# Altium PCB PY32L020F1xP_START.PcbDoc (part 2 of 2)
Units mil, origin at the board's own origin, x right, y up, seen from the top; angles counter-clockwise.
Board outline 1771.65 x 3929.06 mil, 2 copper layers (Top Layer, Bottom Layer), stack 21 mil thick; 129 components, 114 nets, 456 pads, 229 vias.
Unrouted connection lines stored in the file: 5.

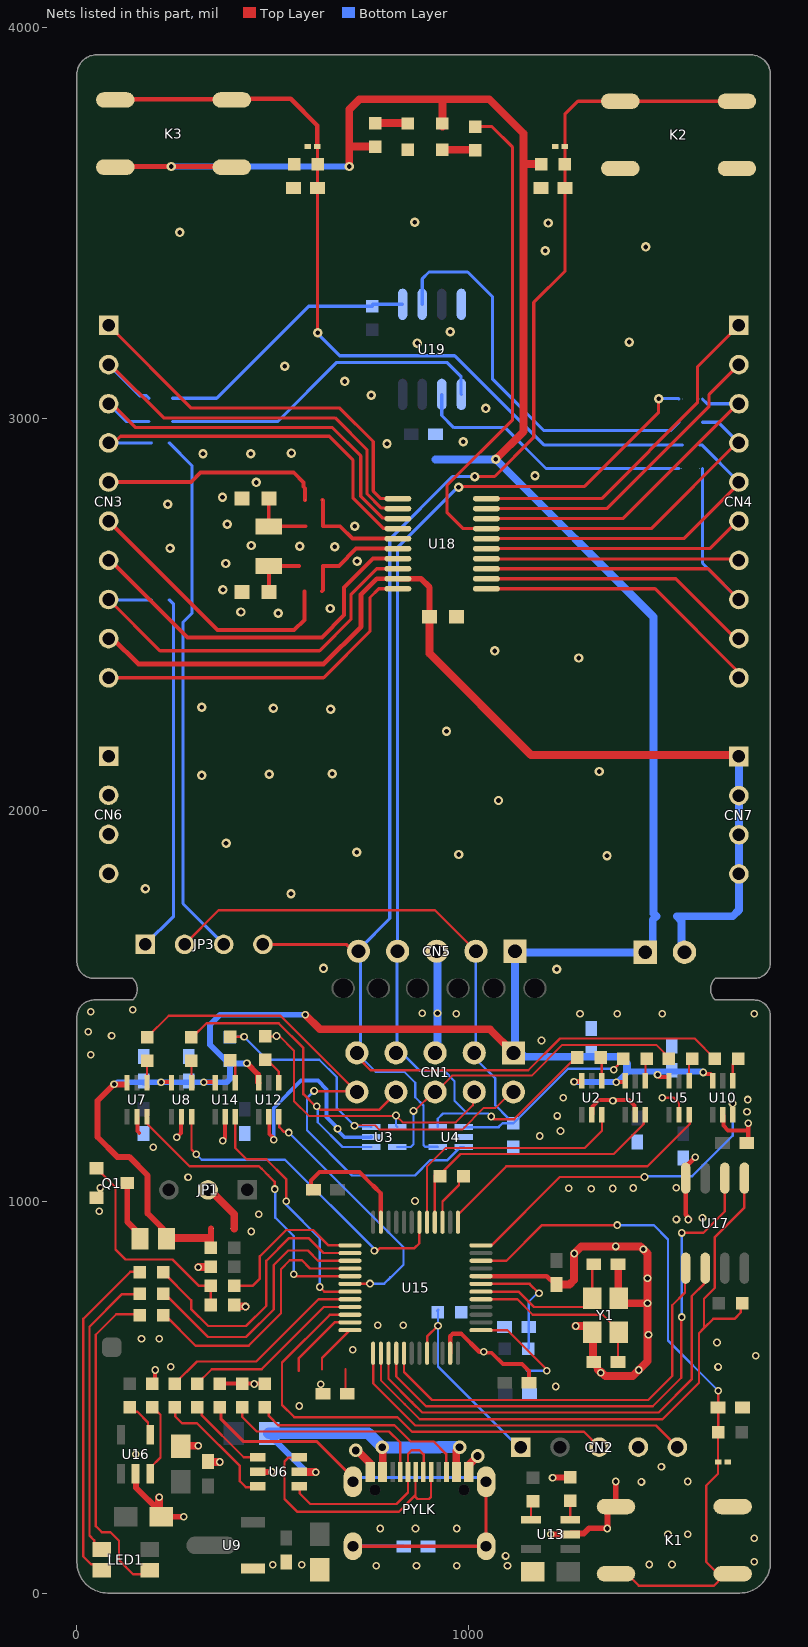
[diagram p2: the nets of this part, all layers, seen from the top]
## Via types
v1: diameter 19.68, hole 11.81, Top Layer to Bottom Layer, tented both sides, 114 vias
v2: diameter 24, hole 12, Top Layer to Bottom Layer, tented both sides, 61 vias
v3: diameter 19.68, hole 11.81, Top Layer to Bottom Layer, 42 vias
v4: diameter 35, hole 20, Top Layer to Bottom Layer, tented both sides, 8 vias
v5: diameter 30, hole 15, Top Layer to Bottom Layer, tented both sides, 2 vias
v6: diameter 40, hole 20, Top Layer to Bottom Layer, tented both sides, 2 vias

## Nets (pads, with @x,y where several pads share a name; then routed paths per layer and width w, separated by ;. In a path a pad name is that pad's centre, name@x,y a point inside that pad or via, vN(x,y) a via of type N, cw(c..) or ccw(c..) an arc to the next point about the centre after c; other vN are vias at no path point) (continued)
GND: C1.1 C2.1 C3.1 C4.1 C5.1 C6.1 C7.1 C8.1 C9.1 C10.1 C11.1 C12.1 C13.1 C14.1 C15.1 C16.1 C17.1 C18.1 C19.1 C20.1 C21.1 C22.1 C23.1 C24.1 C25.1 C26.1 C27.1 C28.1 C29.1 C30.2 C31.1 CN1.5 CN2.4 CN3.7 CN5.3 CN6.1 CN6.2 CN6.3 CN6.4 K1.3 K1.4 K2.3 K2.4 LED_VDD*.2 PYLK.A1 PYLK.A12 PYLK.B1 PYLK.B12 Q1.2 R1.1 R3.2 R5.1 R8.2 R20.1 R21.1 R25.1 R28.2 R30.1 R33.2 R56.1 U1.2 U2.2 U3.2 U4.2 U5.2 U6.2 U7.2 U8.2 U9.1 U10.2 U11.2 U12.2 U13.2 U14.2 U15.8 U15.23 U15.47 U16.2 U17.4 U18.7 U19.4 U20.2 U21.2 Y1.2 Y1.4 | length 5396.9
  Top Layer w6: v1(1495,1265) 1525,1265 1538.06,1251.94 U5.2@1538.06,1221.69
  Top Layer w10: CN3.7@81,2638 85.71,2638 282.96,2440.75 625.55,2440.75 682.73,2497.93 682.73,2568.68 756.63,2642.58 U18.7@819.59,2642.58 ; U7.2@153.55,1216.69 154.54,1215.7 154.54,1180.08 159.36,1175.25 ; R30.1@200,540 v1(200,570) ; C16.1@210,210 210,200 C16.1@215,195 ; v1(255,1164.6) 265.89,1175.49 265.89,1215.32 U8.2@267.26,1216.69 ; C2.1@265,375 C2.1@270,380 ; C3.1@335,336 C3.1@336,335 ; R8.2@365,535 v1@453.95,535 ; v1(372.9,1155.7) 378.59,1161.39 U14.2@378.59,1216.59 ; R20.1@401.52,735.88 R20.1@403.04,737.4 ; v1(453.1,534.15) v1@453.95,535 ; R3.2@480,535 v1@453.95,535 ; U12.2@490.12,1216.69 491.41,1215.4 491.41,1172.62 501.83,1162.2 501.83,1156.83 v1@500,1155 ; C21.1@593.36,1020 603.36,1030 C21.1@604,1030 597.95,1036.05 597.95,1054.14 619.23,1075.42 721.98,1075.42 756.82,1040.58 ; C17.1@628.59,509.5 C17.1@629.59,510.5 ; PYLK.A1@743.31,309.89 PYLK.B12@755.12,309.89 ; PYLK.B1@995.28,309.89 PYLK.A12@1007.09,309.89 ; v1@1039.47,613.56 v1@1039.6,613.69 ; v1@1041.61,614.02 1059.36,614.02 1088.57,584.8 1137.07,584.8 1154.91,566.95 C20.1@1154.87,537.59 ; U2.2@1314.26,1220.75 1317.1,1223.58 1317.1,1242.95 1334.15,1260 v1@1370.02,1260 ; v1(1369.2,1257.6) 1370.02,1258.42 v1@1370.02,1260 ; U1.2@1426.64,1221.69 1424.75,1223.58 1424.75,1245.25 1410,1260 v1@1370.02,1260 ; U10.2@1649.49,1221.69 1651.38,1219.8 1651.38,1193.96 1663.61,1181.72 1715,1181.72
  Top Layer w11: 756.82,1040.58 776.42,1020.98 U15.23@776.42,947.32 ; U15.47@953.58,612.68 953.58,655.91 959.74,662.07 982.08,662.07 1027.87,616.28 v1(1039.35,616.28) ; U15.8@1032.32,809.53 1199.94,809.53 1221.47,788 C22.1@1225.12,788
  Top Layer w12: Q1.2@50.2,1009.8 Q1.2@55.01,1004.99 ; v1(1561.71,954.27) 1566.84,954.27 1555,966.11 1555,1088.88 1579.39,1113.27 v1(1579.39,1113.51) ; C18.1@1711,1150 1715,1154 1715,1181.72 v1(1715,1200)
  Top Layer w15: U16.2@149.48,304.48 150.91,303.04 150.91,269.09 C16.1@210,210 ; C16.1@215,195 v1(272.56,195) ; U6.2@470.66,310.05 472.24,308.47 473.29,309.52 v1(498.08,309.52) ; v1(1210,150) U13.2@1260,150 1262.16,152.16 1294.66,152.16 1308.23,165.74 v1@1354.26,165.74 ; v1(1215,295) R25.1@1260,295 ; v1(1355,165) 1355,209.44 1366.26,220.7 1376.55,220.7 v1(1376.55,285)
  Top Layer w20: C16.1@210,210 v1(210,245) ; C2.1@270,380 273.84,376.16 v1(310,376.16) ; v1(309.83,832.29) 310.59,833.04 341.17,833.04 R21.1@341.93,833.8 ; C3.1@336,335 v1(365,335) ; R20.1@403.04,737.4 403.04,737.12 407.52,732.64 429.94,732.64 v1(430.7,731.87) ; v4(712.08,364.5) 715.53,364.5 PYLK.A1@749.17,330.85 ; CN1.5@915,1380 CN1.5@922.47,1387.47 ; PYLK.A12@1003.89,330.35 v4(1023.55,350) ; C22.1@1220.12,797 1225.12,792 C22.1@1225.12,788 1225.41,788.28 1258.41,788.28 1270.12,800 v1(1270.12,867.57) 1288.1,885.55 1439.57,885.55 1457.58,867.54 v1(1457.58,803.85) 1457.58,740.13 1457.58,592.46 v1(1435.12,570) 1419.85,554.73 1349.89,554.73 v1@1339.64,564.98 ; v1(1273.98,682.29) 1301.06,682.29 Y1.2@1316.66,666.69 1318.39,664.96 1318.39,591.73 C19.1@1320.12,590 1324.12,590 1329.12,585 1329.12,575.5 1330.37,574.25 ; 1330.37,570.63 v1(1337.83,563.18) ; C25.1@1382.12,840 1382.85,839.27 1382.85,754.04 Y1.4@1383.59,753.31 1396.74,740.16 v1(1457.55,740.16)
  Bottom Layer w6: v1@499.26,1157.83 v1(502.89,1157.83)
  Bottom Layer w10: v1(502.89,1157.83) 502.89,1239.49 572.46,1309.06 615.72,1309.06 638,1286.78 638,1215.79 665.89,1187.9 v1(665.89,1185.89) ; v1@665,1183 683.72,1164.28 750.81,1164.28 U3.2@751.54,1165
  Bottom Layer w20: CN1.5@915,1380 921,1386 v3(921,1481) 921,1637.82 CN5.3@919.26,1639.56 ; CN5.3@921,1639.56 CN5.3@921,1642.94
  other v1: 765,70 867.5,70 970,70 1100,70 1462.25,73 1520,73 1730,80 1095,95 1730,140 1510,150 1560,150 775,165 865,165 970,165 1442,284 1560,285 1493,323 150,355 1637.74,577.74 1734,606 1635,640 165,650 210,650 1460.12,660 1447.03,878.1 1376.26,885.55 57.3,975.34 60,1035 1182.35,1167.57 1241.94,1264.95 35,1375 1285,1480 1380,1480 1495,1480 1730,1480 35,1485 143,1490
  other v2: 1226,1593.58 630,1595.58 547,1786.58 175,1799 1354,1883.58 975,1886.58 715,1892.58 381,1915.58 1077,2024.58 319,2088.58 491,2091.58 652,2092.58 1334,2098.58 944,2201.58 648,2257.58 502,2260.58 319,2262.58 1282,2388.58 1067,2406.58 514,2503 419,2506 647,2515 373,2563 380,2630 715.68,2635.32 238,2669 659,2673 569,2674 445,2676 710,2725 384,2730 232,2781 372,2799 458,2837 1170,2854 322,2910 444,2910 548,2912 792,2936 987,2941 1044,3026 752,3060 684,3095 531,3134 869,3193 1411,3195.58 954,3222 1196,3428.58 1453,3438.58 263,3475.58 1204,3499.58 863,3501.58
  other v3: 500.23,72.73 574.48,72.72 568,478 1223.05,527.77 622.75,533.15 239.93,578.18 704.43,621.59 833.63,683.94 768.47,684.5 445.71,923.68 1531.33,954.53 1597.76,958.38 464.86,967.62 863.55,1001.58 1313.59,1033.06 1368.58,1033.45 1256.66,1033.84 1421.24,1034.63 1530.67,1035.55 284,1062 195,1139 1235.29,1180.47 1227.19,1218.9 1711.69,1229.78 1713.32,1260.65 1186.59,1411.54 88.6,1424 29.3,1434.1 969,1480 882,1481
L_USB_CN_DM: PYLK.A7 PYLK.B7 U6.4 | length 510.1
  Top Layer w6: U6.4@568.15,272.6 569.18,271.57 569.18,254.46 596.04,227.6 816.36,227.6 845.67,256.9 845.67,355.67 855,365 875,365 885.71,354.29 885.71,310.57 PYLK.A7@885.04,309.89
L_USB_CN_DP: PYLK.A6 PYLK.B6 U6.6 | length 675.9
  Top Layer w6: U6.6@568.15,347.4 567.26,346.51 540.39,346.51 530.35,336.47 530.35,240.4 563.22,207.53 822.27,207.53 864.95,250.21 ; PYLK.A6@864.95,309.48 864.95,250.21 ; PYLK.B6@904.31,309.48 904.31,245.56 899.06,240.31 870.05,240.31 864.95,245.41 864.95,250.21
LED_BLUE: R9.2 U15.28 | length 675.2
  Top Layer w6: R9.2@220,710 225.04,710 303.26,631.77 438.53,631.77 521.33,714.58 521.33,827.41 543.92,850 575,850 595.79,829.21 U15.28@697.68,829.21
LED_GREEN: R6.2 U15.26 | length 724.3
  Top Layer w6: R6.2@220,820 291.82,748.18 291.82,725.67 335.36,682.13 432.27,682.13 483.48,733.34 483.48,848.48 541.75,906.75 591.91,906.75 630.07,868.58 U15.26@697.68,868.58
LED_RED: R4.2 U15.27 | length 692.2
  Top Layer w6: R4.2@220,765 224.07,765 335.03,654.04 432.13,654.04 502.68,724.59 502.68,837.68 540,875 590,875 616.1,848.9 U15.27@697.68,848.9
NetC1_2: C1.2 PYLK.1 PYLK.2 PYLK.3 PYLK.4 R8.1 | length 1425.4
  Top Layer w8: R8.1@365,475 368.29,471.71 368.29,443.87 424.64,387.52 611.97,387.52 705.12,294.37 PYLK.1@705.12,284.29 ; PYLK.3@705.12,119.73 PYLK.4@1045.28,119.73 PYLK.2@1045.28,284.29
  Bottom Layer w8: PYLK.3@705.12,119.73 834.27,119.73 C1.2@835,119 ; PYLK.1@716.04,295.21 PYLK.2@1034.36,295.21
  Bottom Layer w20: PYLK.1@705.12,284.29 PYLK.1@716.04,295.21 ; PYLK.2@1034.36,295.21 PYLK.2@1045.28,284.29
NetC17_2: C17.2 R31.2 | length 64.1
  Top Layer w6: 686.21,571.75 686.21,513.88 C17.2@690.59,509.5
NetC29_2: C29.2 R49.1 Y2.1 | length 166.6
  Top Layer w10: C29.2@490.5,2796 490,2795.5 Y2.1@490,2724.2 490.8,2725 R49.1@584.24,2725
NetC30_1: C30.1 R50.1 Y2.2 | length 144.1
  Top Layer w10: C30.1@490.5,2557 490.5,2623.3 Y2.2@490,2623.81 566.81,2623.81 567,2624
NetC31_2: C31.2 K3.3 K3.4 R55.1 R56.2 U21.1 | length 2132.1
  Top Layer w8: v2(615,3219) C31.2@615,3589 R56.2@615,3650 U21.1@615,3695
  Top Layer w12: K3.4@92,3815.59 390,3815.59 391.76,3817.35 545.65,3817.35 614.3,3748.7 U21.1@614.3,3695
  Bottom Layer w8: v2(615,3219) 615,3217 671.32,3160.68 964.97,3160.68 1192.65,2933 R55.1@1546.25,2933
NetCN3_5: CN3.5 R39.2 | length 564.9
  Top Layer w10: CN3.5@81,2838 292,2838 316,2862 554,2862 579,2837 579,2826 582.97,2822.03 R39.2@582.97,2792.03
NetCN3_6: CN3.6 R40.2 | length 698.9
  Top Layer w10: CN3.6@81,2738 359,2460 555,2460 580.97,2485.97 580.97,2559.03
NetJP3_1: JP3.1 R51.1 | length 914.5
  Bottom Layer w8: JP3.1@175,1657 247,1729 247,2525.75 R51.1@235.75,2537
NetJP3_3: JP3.3 R44.1 | length 1357.7
  Bottom Layer w8: R44.1@235.75,2938 294,2879.75 294,2503 271,2480 271,1761 JP3.3@375,1657
NetLED1_2: LED1.2 R9.1 | length 846.1
  Top Layer w6: R9.1@160,710 157.67,712.33 100.33,712.33 48,660 48,171 63.8,155.2 85.86,155.2 107.53,133.53 107.53,84.16 143.82,47.87 175.08,47.87 LED1.2@186.02,58.82
NetLED1_3: LED1.3 R6.1 | length 884.3
  Top Layer w6: LED1.3@44.28,58.52 LED1.3@58.98,43.82 ; LED1.3@63.98,58.82 49.28,73.52 36.09,73.52 16,93.61 16,700.34 136.59,820.93 159.07,820.93 R6.1@160,820
NetLED1_4: LED1.4 R4.1 | length 755.1
  Top Layer w6: LED1.4@56.66,98.5 44.36,110.81 44.36,134.74 32,147.09 32,680.34 115.39,763.73 158.73,763.73 R4.1@160,765
NetLED_PA1_2: LED_PA1.2 R53.1 | length 84
  Top Layer w20: LED_PA1.2@933,3687 R53.1@1017,3687
NetLED_VDD*_1: LED_VDD*.1 R38.1 | length 83
  Top Layer w20: R38.1@762,3754.89 LED_VDD*.1@845,3754.89
NetPYLK_A5: PYLK.A5 R1.2 | length 530.3
  Top Layer w6: R1.2@422.49,474.99 422.49,449.82 459.51,412.79 797.58,412.79 825.99,384.38 PYLK.A5@825.99,309.89
NetPYLK_B5: PYLK.B5 R3.1 | length 566
  Top Layer w6: R3.1@480,475 490.31,464.69 490.31,452.34 513.85,428.8 811.11,428.8 852.66,387.24 911.55,387.24 943.17,355.62 943.17,310.82 PYLK.B5@944.1,309.89
NetQ1_1: Q1.1 R19.1 R20.2 | length 559
  Top Layer w6: Q1.1@50,1084.8 51.97,1084.8 63.72,1073.06 63.72,1071.23 98.46,1036.49 98.46,877.34 123.86,851.94 244.45,851.94 311.61,784.78 R19.1@341.53,784.78 ; R20.2@341.52,735.88 R19.1@341.52,784.77
NetQ1_3: Q1.3 R15.1 | length 166.5
  Top Layer w6: Q1.3@125.49,1044.15 Q1.3@128.74,1047.4 ; R15.1@161.54,905 R15.1@161.54,910.91
  Top Layer w15: Q1.3@128.74,1047.4 128.74,948.28 161.54,915.49 R15.1@161.54,905
NetR2_1: R2.1 U1.4 | length 57.9
  Top Layer w6: U1.4@1452.23,1308.31 1452.23,1362.02 R2.1@1455.21,1365
NetR7_1: R7.1 U2.4 | length 57.8
  Top Layer w6: R7.1@1338.06,1365 1340.8,1362.27 U2.4@1340.8,1308.31
NetR10_1: R10.1 U5.4 | length 60.3
  Top Layer w6: U5.4@1563.66,1308.31 1563.66,1356.3 R10.1@1572.35,1365
NetR11_1: R11.1 U6.3 | length 332.9
  Top Layer w6: R11.1@250,475 250.77,474.23 250.77,451.69 268.41,434.05 306.8,434.05 416.24,324.61 416.24,285.87 431.63,270.48 459.74,270.48 U6.3@461.53,272.28
NetR12_1: R12.1 U6.1 | length 227.7
  Top Layer w6: R12.1@308.75,480 319.15,469.6 319.15,453.68 426,346.83 U6.1@471.97,346.83
NetR13_1: R13.1 U7.4 | length 59
  Top Layer w6: R13.1@173.55,1360 179.14,1354.41 U7.4@179.14,1303.31
NetR14_1: R14.1 U8.4 | length 60.8
  Top Layer w6: R14.1@280.94,1360.02 R14.1@290.82,1350.14 ; U8.4@292.86,1303.31 R14.1@292.86,1350.12
NetR18_1: R18.1 U10.4 | length 62.7
  Top Layer w6: U10.4@1675.08,1308.31 1675.08,1350.59 R18.1@1689.49,1365
NetR22_1: R22.1 U12.4 | length 75.3
  Top Layer w6: R22.1@481.63,1362.11 485.62,1362.11 515.71,1332.03 U12.4@515.71,1303.31
NetR24_2: R24.2 U13.4 | length 49.6
  Top Layer w6: U13.4@1160,187.5 1160,230 R24.2@1165,235
NetR25_2: R25.2 U13.3 | length 47.5
  Top Layer w6: U13.3@1260,187.5 R25.2@1260,235
NetR26_1: R26.1 U14.4 | length 62.8
  Top Layer w6: R26.1@391.2,1360.7 404.28,1347.62 U14.4@404.28,1303.31
NetR27_2: R27.2 U15.1 | length 263.8
  Top Layer w6: U15.1@1032.32,671.73 1099.27,671.73 1200,571 v3(1200,568)
  Bottom Layer w6: R27.2@1149.03,569.03 1150.05,568 v3(1200,568)
NetR29_2: R29.2 U16.4 | length 96.1
  Top Layer w6: R29.2@135,475 147,463 154.44,463 181.5,435.94 181.5,411 U16.4@187.5,405
NetR30_2: R30.2 U16.3 | length 190
  Top Layer w6: U16.3@187.5,305 187.5,320 213.56,346.06 213.56,455.68 207.24,462 206,462 R30.2@193,475
NetR31_1: R31.1 U15.36 | length 129.6
  Top Layer w6: 626.21,571.75 626.21,600.26 U15.36@697.68,671.73
NetR33_1: R33.1 U15.35 | length 201.4
  Top Layer w6: 566.96,567.4 566.96,600.38 658,691.42 U15.35@697.68,691.42
NetR43_1: R43.1 R45.1 U19.1 | length 685.3
  Bottom Layer w8: 244,3052 357,3052 592,3287 R43.1@755,3287 ; R43.1@755,3292 U19.1@832,3292
NetR46_1: R46.1 U19.2 | length 1028.3
  Bottom Layer w8: U19.2@882,3292 882,3357 899.53,3374.53 997.98,3374.53 1062.02,3310.49 1062.02,3100.21 1192.97,2969.26 1516.38,2969.26 1538,2990.88
NetR47_2: R47.2 U19.6 | length 716
  Bottom Layer w8: U19.6@932,3062 932,3008 963,2977 1093.91,2977 1198.16,2872.75 1537.99,2872.75
NetR48_2: R48.2 U19.5 | length 860.8
  Bottom Layer w8: 244.01,2992.26 512.34,2992.26 663.83,3143.76 944.99,3143.76 981.41,3107.35 981.41,3062.59 U19.5@982,3062
OSCIN32: R39.1 R49.2 U18.5 | length 271.5
  Top Layer w10: R39.1@627.75,2792 629.02,2790.73 R49.2@629.02,2724.97 672.03,2724.97 703.59,2693.41 U18.5@819.94,2693.41
OSCOUT32: R40.1 R50.2 U18.6 | length 275.4
  Top Layer w10: 625.75,2559 629.02,2562.26 R50.2@629.02,2623.97 668.97,2623.97 712.82,2667.82 U18.6@819.94,2667.82
PA0: CN4.5 R55.2 U18.16 | length 846.6
  Top Layer w8: U18.16@1046,2693.41 1550.52,2693.41 1691,2833.89 CN4.5@1691,2838
  Bottom Layer w8: R55.2@1591.03,2933.03 1595.97,2933.03 CN4.5@1691,2838
PA1: CN4.4 R46.2 R53.2 U18.17 | length 2093.9
  Top Layer w8: R53.2@1018,3746 1059.89,3746 1113,3692.89 1113,2997 945,2829 945,2761 987,2719 U18.17@1046,2719.01 1467.21,2719 1686.21,2938 CN4.4@1691,2938
  Bottom Layer w8: 1598,2990.88 1638.12,2990.88 1680,2949 1691,2949 CN4.4@1691,2938
PA3: CN4.2 U18.19 | length 822.4
  Top Layer w8: U18.19@1046,2770.19 1353.61,2770.18 1615,3031.57 1615,3062 CN4.2@1691,3138 CN4.2@1691,3130.8
PA4: CN4.1 U18.20 | length 881.8
  Top Layer w8: U18.20@1046,2795.78 1340.36,2795.77 1585,3040.41 1585,3132 CN4.1@1691,3238
PA5: CN3.1 U18.1 | length 996.2
  Top Layer w8: CN3.1@81,3238 292.13,3026.87 671.53,3026.87 757,2941.4 757,2814.88 776.11,2795.77 U18.1@819.94,2795.78
PA6: CN3.2 R45.2 U18.2 | length 1095.6
  Top Layer w8: CN3.2@81,3138 85.61,3138 221.82,3001.79 659.68,3001.79 741,2920.46 741,2808.25 777.86,2771.39 818.73,2771.39 U18.2@819.94,2770.19
  Bottom Layer w8: CN3.2@81,3138 160.69,3058.31 177.69,3058.31 184,3052
PA7: CN3.3 R48.1 U18.3 | length 1042.9
  Top Layer w8: CN3.3@81,3038 89.2,3038 150.08,2977.12 652.76,2977.12 725,2904.88 725,2801.63 780.83,2745.8 818.73,2745.8 U18.3@819.94,2744.6
  Bottom Layer w8: CN3.3@81,3038 126.74,2992.26 184.01,2992.26
PB0: CN4.6 U18.15 | length 674.1
  Top Layer w8: U18.15@1046,2667.82 1616.39,2667.82 1686.57,2738 CN4.6@1691,2738
PB1: CN4.7 U18.14 | length 647.8
  Top Layer w8: U18.14@1046.39,2642.61 U18.14@1046,2642.23 1047.21,2641.02 1687.98,2641.02 CN4.7@1691,2638 CN4.7@1690.61,2637.61
PB2: CN4.8 R47.1 U18.13 | length 1050.8
  Top Layer w8: U18.13@1046,2616.64 1612.36,2616.64 CN4.8@1691,2538
  Bottom Layer w8: 1597.99,2872.75 1597.99,2631.01 CN4.8@1691,2538
PB3: CN4.9 U18.12 | length 708.4
  Top Layer w8: U18.12@1046,2591.05 1530,2591.05 1683.05,2438 CN4.9@1691,2438
PB4: CN4.10 U18.11 | length 747.1
  Top Layer w8: U18.11@1046,2565.46 1477,2565.46 1691,2351.46 CN4.10@1691,2338
PB5: CN3.10 U18.10 | length 883.9
  Top Layer w8: CN3.10@81,2338 630.08,2338 748.55,2456.48 748.55,2543.11 770.9,2565.46 U18.10@819.94,2565.46
PB6: CN3.8 R51.2 U18.8 | length 1027.7
  Top Layer w8: CN3.8@81,2538 212,2407 620,2407 699.73,2486.73 699.73,2550.34 766.03,2616.64 U18.8@819.94,2616.64
  Bottom Layer w8: CN3.8@81,2538 82.03,2536.97 R51.2@190.97,2536.97
PC0: CN3.4 R44.2 U18.4 | length 1010.6
  Top Layer w8: CN3.4@81,2938 94.21,2938 111.21,2955 644.66,2955 705,2894.66 705,2797.63 782.67,2719.96 818.97,2719.96 U18.4@819.94,2719.01
  Bottom Layer w8: CN3.4@81,2938 R44.2@190.97,2937.97
PYLK_BOOT0: CN2.1 R28.1 U15.44 | length 514.4
  Top Layer w6: U15.44@894.53,612.68 894.53,655.07 v1(922.21,682.75)
  Bottom Layer w6: R28.1@923.26,724.4 920.49,721.63 922.21,719.9 v1(922.21,682.75) 922.21,578.79 CN2.1@1124,377
PYLK_KEY: C6.2 K1.1 K1.2 R16.1 U11.1 U15.10 | length 1804.3
  Top Layer w6: U15.10@1032.32,848.9 1097.14,848.9 1188.24,940 v1(1380,940) ; K1.2@1376.55,49 1405.25,49 1435.5,18.75 1627.36,18.75 1639.02,30.41 1639.02,34.51 K1.1@1653.51,49 ; v1(1638,517) C6.2@1638,474 R16.1@1638,411 1637.7,410.7 U11.1@1637.7,335 1637.7,304.7 1607.3,274.3 1607.3,80 1638.3,49 K1.1@1653.51,49 ; K1.1@1674.55,49 K1.1@1653.51,49
  Bottom Layer w6: v1(1380,940) 1473.52,940 1510,903.52 1510,645 v1(1638,517)
PYLK_NRST: C24.2 R36.1 U15.7 | length 313.8
  Top Layer w6: U15.7@1032.32,789.84 1156.36,789.84 v1(1180.4,765.8)
  Bottom Layer w6: R36.1@1153,624 1154.12,625.12 C24.2@1154.12,680 1154.12,744 1175.92,765.8 v1(1180.4,765.8)
PYLK_OSCIN: C19.2 U15.5 Y1.3 | length 465.6
  Top Layer w6: U15.5@1032.32,750.47 1125.05,750.47 1164.42,711.1 1343.11,711.1 1383.59,670.63 Y1.3@1383.59,666.69 1382.12,665.22 C19.2@1382.12,590
PYLK_OSCOUT: C25.2 U15.6 Y1.1 | length 399.8
  Top Layer w6: U15.6@1032.32,770.16 1127.99,770.16 1167.36,730.79 1297.03,730.79 1316.66,750.41 Y1.1@1316.66,753.31 1316.66,836.54 C25.2@1320.12,840
PYLK_SPI_CS: R35.1 U15.38 U17.1 | length 1667.6
  Top Layer w5: U15.38@776.42,612.68 776.42,543.62 837.66,482.38
  Top Layer w6: 837.66,482.38 875.95,444.09 1495.51,444.09 1588.88,537.47 1588.88,663.88 1601.77,676.77 ; R35.1@1700,740 1695.62,735.62 1695.62,716.69 1679.36,700.42 1625.42,700.42 1601.77,676.77 ; U17.1@1705,1060 1705,985 1629.69,909.69 1629.69,780.01 1601.77,752.09 1601.77,676.77
PYLK_SPI_MISO: U15.40 U17.2 | length 1437.2
  Top Layer w6: U15.40@815.79,612.68 815.79,553.3 891.8,477.3 1471,477.3 1543.9,550.2 1543.9,703.9 v1(1545,705) ; v1(1545,920) 1600,920 1655,975 U17.2@1655,1060
  Bottom Layer w6: v1(1545,705) v1(1545,920)
PYLK_SPI_MOSI: U15.41 U17.5 | length 1077.9
  Top Layer w6: U15.41@835.47,612.68 835.47,564.49 906.66,493.3 1459.42,493.3 1520.53,554.41 1520.53,735.09 1553.13,767.69 1553.13,828.13 U17.5@1555,830
PYLK_SPI_SCK: U15.39 U17.6 | length 1208.9
  Top Layer w6: U15.39@796.1,612.68 796.1,547.36 856.32,487.14 882.17,461.3 1486.07,461.3 1570.21,545.44 1570.21,758.06 1601.94,789.79 1601.94,826.94 U17.6@1605,830
SWCLK: CN4.3 R52.2 U18.18 | length 876.5
  Top Layer w8: U18.18@1046,2744.6 1394.41,2744.59 1687.82,3038 CN4.3@1691,3038
  Bottom Layer w8: 1598,3049.94 1609.94,3038 CN4.3@1691,3038 CN4.3@1691,3050
SWD_SCK: CN2.5 U15.37 | length 921.6
  Top Layer w6: U15.37@756.73,612.68 756.73,535.75 864.48,428 1479,428 CN2.5@1534,373
SWD_SDA: CN2.3 U15.34 | length 1187.1
  Top Layer w6: U15.34@697.68,711.1 646.11,711.1 524.05,589.04 524.05,480.71 555.57,449.2 818.75,449.2 855.95,412 1295,412 CN2.3@1334,373
T_RESET: C28.2 CN1.9 CN5.5 JP3.4 K2.1 K2.2 R18.2 R42.2 U4.4 U20.1 | length 4742.8
  Top Layer w6: CN1.9@722.78,1362.78 750.2,1335.36 1152.91,1335.36 1233.99,1416.44 1578.06,1416.44 R18.2@1629.49,1365
  Top Layer w8: JP3.4@475,1657 688.01,1657 705.44,1639.56 CN5.5@719.26,1639.56 ; v2(1016,2852) 1067,2852 1167,2952 1167,3297 1247,3377 C28.2@1247,3589 1247,3649 R42.2@1246,3650 1246.3,3650.3 U20.1@1246.3,3695 1246.3,3777.3 1279.7,3810.7 K2.1@1388,3810.7 K2.2@1686,3810.7
  Bottom Layer w6: CN1.9@715,1380 763.22,1331.78 836.02,1331.78 864.1,1303.69 864.1,1266.42 885.15,1245.37 885.15,1144.31 889.61,1139.85 921.09,1139.85 U4.4@921.54,1139.41
  Bottom Layer w8: CN1.9@715,1380 724.04,1389.04 CN5.5@724.04,1634.78 ; CN5.5@719.26,1639.56 CN5.5@724.15,1644.45 ; CN5.5@722.3,1646.3 799,1723 799,2692 959,2852 v2(1016,2852)
T_RESETa: U10.3 U15.12 | length 870.1
  Top Layer w6: U15.12@1032.32,888.27 1058.79,888.27 1233.47,1062.96 1321.53,1062.96 v1(1449.91,1062.96) ; v1(1674.82,1250.7) 1675.08,1250.44 U10.3@1675.08,1221.69
  Bottom Layer w6: v1(1449.91,1062.96) 1451.65,1064.7 1571.4,1064.7 1674.82,1168.11 v1(1674.82,1250.7)
T_RTCK_DTRa: U5.3 U15.13 | length 731.2
  Top Layer w6: U15.13@973.27,947.32 973.27,966.57 1096.7,1090 1456.99,1090 1565.18,1198.19 1565.18,1220.16 U5.3@1563.66,1221.69
T_RTCK_VCP_DTR: CN1.6 R10.2 U3.5 | length 868.3
  Top Layer w5: v1(859.81,1231.67) 863.24,1231.67 911.57,1280 CN1.6@915,1280 916.63,1280 958.49,1321.86 1161.73,1321.86 1240.3,1400.44 1479.98,1400.44 1500.35,1380.07 1500.35,1377 R10.2@1512.35,1365
  Bottom Layer w6: U3.5@818.46,1139.41 852.51,1139.41 859.81,1146.71 v1(859.81,1231.67)
T_TCK_SWCLK: CN1.7 CN5.4 R7.2 R52.1 U4.5 | length 2916
  Top Layer w6: CN1.7@820,1390 CN1.7@821.35,1391.35 ; v1(1058.5,1217.32) 1065.14,1210.69 1116.96,1210.69 1271.28,1365 R7.2@1278.06,1365
  Top Layer w8: v2(974.97,2825.03) 976.94,2827 1296.82,2827 1486,3016.18 v2(1486,3051)
  Bottom Layer w6: CN1.7@822.5,1387.5 875.47,1334.53 937.65,1334.53 964.6,1307.57 964.6,1257.54 997.14,1225 ; U4.5@921.54,1190.59 921.54,1211.54 935,1225 997.14,1225 ; v1(1058.5,1217.32) 1050.82,1225 997.14,1225
  Bottom Layer w8: CN1.7@815,1380 817.79,1382.79 817.79,1638.1 CN5.4@819.26,1639.56 819.26,2671.26 973.03,2825.03 v2(974.97,2825.03) ; v2(1486,3051) 1536.94,3051 1538,3049.94
T_TCK_SWCLKa: U2.3 U15.17 | length 668.1
  Top Layer w5: U15.17@894.53,947.32 894.53,1089.76 941.77,1137
  Top Layer w6: 941.77,1137 1047.62,1137 1297.43,1137 1341.41,1180.98 1341.41,1221.08 U2.3@1340.8,1221.69
T_TDI_VCP_TX: CN1.4 R22.2 U3.4 | length 783.1
  Top Layer w5: R22.2@481.63,1422.11 517.9,1422.11 554.54,1385.48 554.54,1256.62 592.29,1218.86 v1@815,1218.86 ; R22.2@481.63,1425.11 R22.2@483.13,1423.61 ; v1@815.02,1218.86 831.78,1202.11 967.76,1202.11 1011.56,1245.9 1011.56,1276.56 CN1.4@1015,1280
  Bottom Layer w5: v1@815.06,1219.94 815.06,1194 U3.4@818.46,1190.59
  other v1: 815,1220
  other v3: 509.96,1422.98
T_TDI_VCP_TXa: U12.3 U15.30 | length 672.4
  Top Layer w6: U12.3@515.71,1216.69 516.93,1215.47 516.93,1190.37 529.24,1178.06 539.56,1178.06 v1(541.31,1176.31) ; U15.30@697.68,789.84 748.02,789.84 v1(748.76,790.58)
  Bottom Layer w6: v1(541.31,1176.31) 834.09,883.53 834.09,838.92 801.56,806.38 800.71,806.38 784.91,790.58 v1(748.76,790.58)
T_TDO_SWO: CN1.10 R13.2 U4.3 | length 1333.3
  Top Layer w6: R13.2@179.66,1420.08 234.47,1474.9 520.1,1474.9 CN1.10@708.51,1286.49 ; v1(605.87,1282.75) 606.54,1282.08 704.1,1282.08 CN1.10@708.51,1286.49 ; CN1.10@715,1280 CN1.10@708.51,1286.49
  Bottom Layer w6: v1(605.87,1282.75) 587.83,1264.72 587.83,1182.08 703.06,1066.86 863.29,1066.86 902.42,1105.99 946.45,1105.99 979.88,1139.41 U4.3@988.46,1139.41 U4.3@986.15,1137.1
T_TDO_SWOa: U7.3 U15.29 | length 807.7
  Top Layer w6: U7.3@179.14,1216.69 179.14,1198.86 287.46,1090.54 465.08,1090.54 471.63,1084 472.01,1084 489,1067.01 489,1066.63 504.93,1050.7 504.93,1032.69 v1(505.62,1032) ; v1(553.88,814.33) 558.68,809.53 641.55,809.53 U15.29@697.68,809.53
  Bottom Layer w6: v1(505.62,1032) 506.95,1030.68 506.95,958.93 553.88,912 v1(553.88,814.33)
T_TMS_SWDIO: CN1.3 CN5.2 JP3.2 R2.2 R5.2 U4.1 | length 1758.6
  Top Layer w6: JP3.2@275,1657 362,1744 914.82,1744 CN5.2@1019.26,1639.56 ; CN1.3@1019.37,1366.19 CN1.3@1025.56,1360 ; v1@1371.62,1338.31 1382.21,1348.9 1382.21,1352 R2.2@1395.21,1365
  Bottom Layer w6: U4.1@988.77,1190.29 1077.29,1190.29 1087,1200 R5.2@1115,1200 1254.25,1339.25 1369.25,1339.25 v1(1371.43,1337.07) ; CN1.3@1015,1380 1019,1384 1019,1639.3 CN5.2@1019.26,1639.56 ; CN5.2@1019,1639.56 CN5.2@1019,1644.94 ; CN1.3@1023.59,1359.7 1068.86,1314.42 1068.86,1246.14 R5.2@1101.08,1213.92
T_TMS_SWDIOa: R32.1 U1.3 U15.16 | length 723.8
  Top Layer w6: U15.16@914.21,947.32 R32.1@914.21,1067.37 ; R32.1@927.46,1064.37 927.46,1068.99 980.12,1121.65 1036.7,1121.65 1371.22,1121.65 1448.34,1198.77 1448.34,1217.8 U1.3@1452.23,1221.69
T_TMS_SWDIOa_OUT: R32.2 U15.15 | length 143.2
  Top Layer w6: U15.15@933.9,947.32 933.9,1000.64 975.82,1042.56 R32.2@975.82,1073.16
T_TRST_RTSa: U8.3 U15.18 | length 840.3
  Top Layer w6: U8.3@292.86,1216.69 292.86,1132.86 v1(304.82,1120.9) ; v1(759.92,874.35) 763.83,870.44 774.54,881.16 862.39,881.16 874.84,893.6 U15.18@874.84,947.32
  Bottom Layer w6: v1(304.82,1120.9) 318.81,1106.91 531.65,1106.91 759.92,878.64 v1(759.92,874.35)
T_TRST_VCP_RTS: CN1.8 R14.2 U3.1 | length 935
  Top Layer w6: R14.2@292.3,1420.1 295.54,1420.1 331.24,1455.8 515.25,1455.8 578.58,1392.47 578.58,1274.56 609.4,1243.73 v1(612.86,1243.73) 621.6,1235 772.67,1235 820,1282.33 CN1.8@820,1290
  Bottom Layer w6: v1(612.86,1243.73) 615,1241.6 615,1202.6 678.19,1139.41 U3.1@751.54,1139.41
T_VCP_RX: CN1.2 R23.1 R26.2 U3.3 | length 1000.9
  Top Layer w5: v1(708.97,1193.74) 710.23,1195 761.42,1195 772.45,1183.97 983.91,1183.97 1039.3,1239.36 1069.36,1239.36 CN1.2@1120,1290
  Top Layer w6: R26.2@391.2,1420.7 426.7,1420.7 v3(427,1421) ; R26.2@391.2,1431.85 R26.2@391.32,1431.97
  Bottom Layer w6: R23.1@391,1420 392,1421 v3(427,1421) 485.72,1362.28 619.26,1362.28 664.05,1317.5 664.05,1238.66 v1(708.97,1193.74) 708.23,1193 708.23,1191.77 750.36,1191.77 U3.3@751.54,1190.59
T_VCP_RXa: U14.3 U15.31 | length 636
  Top Layer w6: U14.3@404.28,1216.69 404.28,1137.29 433.27,1108.3 483.54,1108.3 534.4,1057.43 534.4,1001.38 v1(535,1000.78) ; v1(620.4,781.75) 631.99,770.16 U15.31@697.68,770.16
  Bottom Layer w6: v1(535,1000.78) 535,991.42 620.4,906.02 v1(620.4,781.75)
TVDD: C12.2 C13.2 C14.2 C15.2 CN1.1 CN5.1 JP2.1 K3.1 K3.2 LED_PA1.1 R15.2 R17.2 R23.2 R34.2 R37.1 R38.2 R41.1 R42.1 U1.6 U2.6 U5.6 U7.6 U8.6 U10.6 U12.6 U14.6 | length 7557.8
  Top Layer w6: U8.6@241.67,1303.31 U8.6@244.56,1306.2 ; U14.6@353.1,1303.31 U14.6@355.99,1306.2
  Top Layer w10: v1(215,1305) 239.98,1305 U8.6@241.67,1303.31 ; v3@325,1305 351.41,1305 U14.6@353.1,1303.31 ; v3(1377.88,1305.09) 1399.07,1305.09 1399.16,1305 1401.05,1306.89 U1.6@1401.05,1308.31 ; v1(1483.29,1324.06) 1488.61,1318.74 1512.47,1318.74 U5.6@1512.47,1308.31 ; v1@1608.68,1326.1 1618.91,1326.1 1623.9,1321.1 U10.6@1623.9,1308.31
  Top Layer w12: K3.2@92,3643.89 v2(241,3643.89) K3.1@390,3643.89 ; v1@1270.9,1306.9 U2.6@1289.01,1306.9
  Top Layer w15: v1(95,1300) 52.5,1257.5 52.5,1164.78 103.07,1114.2 133.42,1114.2 180.53,1067.09 180.53,969.95 220.52,929.96 220.52,912.95 R15.2@228.46,905 R15.2@230.24,906.78 ; v1@95.63,1299.37 U7.6@127.35,1299.37 ; 338.07,906.78 342.08,902.77 ; R17.2@342.08,874.02 342.08,902.77 ; 342.08,931.52 342.08,902.77 ; v3(434.28,1353.05) 462.84,1324.49 462.84,1305 U12.6@464.53,1303.31 ; v1(1270,1306) v1@1270.9,1306.9
  Top Layer w20: R15.2@230.24,906.78 338.07,906.78 ; v3(583.63,1477.38) 620.91,1440.1 1054.9,1440.1 CN1.1@1115,1380 ; 695.91,3694.89 R38.2@762,3694.89 ; v2(696,3644) 695.8,3644.2 695.8,3789.69 722,3815.89 934,3815.89 ; LED_PA1.1@934,3745.89 934,3815.89 ; v2(1070.25,2896) 1139.59,2965.34 ; 1141,2966.75 1141,3728 1053.11,3815.89 934,3815.89 ; 1143,3650 R42.1@1186,3650
  Bottom Layer w15: v1(95,1300) 98.79,1300 103.67,1304.88 C15.2@168.87,1304.88 ; C15.2@170,1303.74 C15.2@168.87,1304.88 ; v1@214.88,1304.88 C15.2@168.87,1304.88 ; v1(215,1305) v3(323.77,1305) 383,1305 391,1313 R23.2@391,1360 380.76,1360 340,1400.76 340,1452 365.38,1477.38 v3(583.63,1477.38) ; v2(241,3643.89) 241.06,3643.94 695.94,3643.94 v2(696,3644) ; R23.2@391,1353.05 v3(434.28,1353.05) ; v1@1270.38,1305.62 v3@1377.36,1305.62 ; v3(1377.88,1305.09) 1379.15,1305.09 1381.49,1307.43 1382.09,1307.43 1406.58,1331.92 ; 1404.72,1331.92 1598.08,1331.92 v1(1600,1330)
  Bottom Layer w20: 916,2896 v2(1070.25,2896) 1473,2493.25 1473,1736.25 R37.1@1480.25,1729 1470.95,1719.7 1470.95,1655.95 JP2.1@1452,1637 ; CN1.1@1118.94,1383.94 CN5.1@1118.94,1639.24 ; CN1.1@1122.04,1388.26 1143.46,1370 1386.9,1370 1404.72,1352.18 1404.72,1331.92 ; CN5.1@1122.76,1636.06 JP2.1@1451.06,1636.06
TVDD*: JP1.2 R34.1 | length 129
  Top Layer w20: JP1.2@335,1030 339.73,1030 402.08,967.65 402.08,931.52
TVDD_DISCHARGE_EN: R19.2 U15.25 | length 404.9
  Top Layer w6: R19.2@401.53,784.78 448.51,784.78 467.48,803.75 467.48,860.55 534.58,927.66 603.61,927.66 643,888.27 U15.25@697.68,888.27
USB_DM: R11.2 U15.32 | length 536.9
  Top Layer w6: R11.2@250,535 306.4,591.4 458.28,591.4 617.36,750.47 U15.32@697.68,750.47
USB_DP: R12.2 U15.33 | length 471.3
  Top Layer w6: R12.2@307.5,535 344.45,571.95 471.73,571.95 630.56,730.79 U15.33@697.68,730.79
VBUS_PYLK: F1.1 PYLK.A4 PYLK.A9 PYLK.B4 PYLK.B9 U6.5 | length 806.9
  Top Layer w10: PYLK.A4@774.81,309.89 PYLK.B9@786.62,309.89 ; PYLK.B4@963.78,309.88 PYLK.A9@975.6,309.88
  Top Layer w20: U6.5@568.15,310 568.98,309.17 609.58,309.17 v1(610.2,308.55) ; PYLK.B9@781.05,327.56 v4@781.05,371.45 ; PYLK.B4@969,328.77 v4@969,362.58
  Bottom Layer w15: F1.1@490.98,408 490.98,404.75 587.18,308.55 v1(610.2,308.55)
  Bottom Layer w20: v4@977.13,372.01 v4(977.62,372.5)
  Bottom Layer w30: F1.1@490.98,408 744.5,408 v4(780,372.5) ; v4@780.49,372.01 925.68,372.01 ; 925.68,373.41 v4@976.72,373.41
VDD: C27.2 CN3.9 CN7.1 CN7.2 CN7.3 CN7.4 JP2.2 R37.2 U18.9 | length 3003.8
  Top Layer w12: CN3.9@81,2438 91.99,2438 156.72,2373.26 630.86,2373.26 725.77,2468.17 725.77,2550.92 765.89,2591.05 U18.9@819.94,2591.05
  Top Layer w15: U18.9@819.94,2591.05 878.95,2591.05 901,2569 C27.2@901,2494
  Top Layer w20: C27.2@901,2494 901,2400 1160,2141 CN7.1@1689.01,2141
  Bottom Layer w20: JP2.2@1552,1637 1544.35,1644.65 1544.35,1716.65 1532,1729 1675,1729 1691,1745 ; CN7.4@1691,1838 1691,1745 ; CN7.3@1691,1938 1691,1745 ; CN7.1@1691,2138 1691,2038 1691,1745
pads on no net: PYLK. PYLK.A8 PYLK.B8 U15.42 U15.45

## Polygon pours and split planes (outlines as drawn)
GND on Top Layer "NONET_L-01_P-001" (solid, remove dead copper, pour order 4): 8.64,3929.06 1773.49,3929.06 1773.49,0 0,0
GND on Bottom Layer "NONET_L-01_P-001" (solid, remove dead copper, pour order 3): 0.11,3929.06 1773.49,3929.06 1773.49,0 -8.53,0

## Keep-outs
Keep-Out Layer:
  lines w8: 0,78.74 ccw(c78.74,78.74) 78.74,0 1692.91,0 ccw(c1692.91,78.74) 1771.65,78.74 1771.65,1473.35 ccw(c1730,1473.35) 1730,1515 1630,1515 cw(c1657.5,1542.5) 1630,1570 1730,1570 ccw(c1730,1611.65) 1771.65,1611.65 1771.65,3855.75 1771.65,3879.06 ccw(c1721.65,3879.06) 1721.65,3929.06 1692.91,3929.06 78.74,3929.06 50,3929.06 ccw(c50,3879.06) 0,3879.06 0,3859.09 0,1615 ccw(c43.75,1613.75) 42.5,1570 142.5,1570 cw(c115,1542.5) 142.5,1515 42.5,1515 ccw(c43.75,1471.25) 0,1470 0,78.74 ; 215,1515 cw(c242.5,1542.5) 215,1570 565,1570 585,1570 cw(c557.5,1542.5) 585,1515 565,1515 215,1515 ; 1260,1515 cw(c1287.5,1542.5) 1260,1570 1280,1570 1560,1570 cw(c1532.5,1542.5) 1560,1515 1280,1515 1260,1515

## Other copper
Top Layer:
  pour cut-out: 1655,1370 1665,1370 1665,1360 1655,1360
  pour cut-out: 275,490 285,490 285,480 275,480
  pour cut-out: 275,525 285,525 285,515 275,515
  pour cut-out: 330,525 335.5,525 335.5,503 330,503
  pour cut-out: 330,490 340,490 340,480 330,480
  region net 5V_USB_CHGR: 385,235 395,245 420,245 465,200 510,200 530,180 660,180 660,120 515,120 515,140 490,165 435,165 400,200 385,215
  region net 3V3_PYLK: 240,315 290,315 310,295 355,295 360,290 360,250 345,235 345,165 362.5,147.5 355,140 293.39,140 293.39,153.49 305,165.1 305,230 280,255 240,255
  region net 3V3_PYLK: 1095,155 1105,165 1125,165 1135,155 1135,130 1140,125 1185,125 1190,120 1190,105 1185,100 1130,100 1095,135
  region net 3V3_USB_PYLK: 1227.5,120 1300,120 1315,135 1335,135 1345,125 1345,105 1330,90 1315,90 1290,65 1290,25 1225,25 1225,118.33
  pour cut-out: 390,495 400,495 400,485 390,485
  pour cut-out: 445,495 455,495 455,485 445,485
  pour cut-out: 1627.43,1037 1637.43,1037 1637.43,1027 1627.43,1027
  pour cut-out: 1675,1075 1685,1075 1685,1065 1675,1065

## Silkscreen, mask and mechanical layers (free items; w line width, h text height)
Top Overlay:
  drawing of 1057 lines, arcs and shapes, not listed
  text "NRST" at 1483,3504.64 h60
  text "USER_PA0" at 107,3502.66 h60
  text "1" at 74,3292 h50
  text "20" at 1664.96,3290.54 h50
  text "A4" at 1513.96,3234 h50
  text "A5" at 179.96,3227.53 h50
  text "PY32L020F1xP_START_V2.0" at 604,3176.79 h60
  text "A6" at 179.96,3127.94 h50
  text "A3" at 1513.96,3127.54 h50
  text "2025-05" at 703.96,3047.06 h60
  text "A7" at 179.96,3028.99 h50
  text "A2" at 1513.96,3028 h50
  text "C0" at 180,2928.93 h50
  text "A1" at 1513.96,2917 h50
  text "C1" at 180,2828.87 h50
  text "A0" at 1513.96,2823.54 h50
  text "B7" at 180,2729.92 h50
  text "B0" at 1514,2721.54 h50
  text "GND" at 180,2629.86 h50
  text "B1" at 1514,2624 h50
  text "B6" at 180,2530.27 h50
  text "B2" at 1514,2525.19 h50
  text "VDD" at 180,2431.32 h50
  text "B3" at 1514,2422.17 h50
  text "B5" at 180,2331.83 h50
  text "B4" at 1514,2319.78 h50
  text "10" at 60,2260.54 h50
  text "11" at 1669,2259 h50
  text "GND" at 180,2131.71 h50
  text "VDD" at 1514,2121 h50
  text "GND" at 180,2031.65 h50
  text "VDD" at 1514,2018 h50
  text "GND" at 180,1931.59 h50
  text "VDD" at 1514,1918 h50
  text "GND" at 180,1831.54 h50
  text "VDD" at 1514,1817 h50
  text "PB6" at 129,1712.54 h50
  text "SWD" at 225,1712.54 h50
  text "PC0" at 344,1712.54 h50
  text "NRST" at 442,1712.54 h50
  text "NRST" at 630,1710.54 h50
  text "SWC" at 760,1710.54 h50
  text "GND" at 870,1710.54 h50
  text "SWD" at 985,1710.54 h50
  text "VDD*" at 1100,1710.51 h50
  text "VDD*" at 1377,1701 h40
  text "VDD" at 1507,1698 h40
  text "IDD" at 1607,1624 h40
  text "NRST" at 670,1445.43 h40
  text "SWC" at 790,1445.43 h40
  text "GND" at 896.86,1445.43 h40
  text "SWD" at 996.31,1445.43 h40
  text "VDD*" at 1090,1445.46 h40
  text "DTR" at 896.86,1175.88 h40
  text "TX" at 996.31,1175.88 h40
  text "RX" at 1090,1175.88 h40
  text "SWO" at 670,1175.43 h40
  text "RTS" at 790,1175.43 h40
  text "VDD_SEL" at 493,1088.66 h60
  text "5V" at 208,1075.54 h50
  text "3V3" at 403,1075.54 h50
  text "VDD*" at 282,1075 h50
  text "5V_USB" at 48.18,563.82 h50 r90
  text "CLK" at 1494,423.54 h50
  text "GND" at 1382,422.54 h50
  text "BOT" at 1079,421.54 h50
  text "DIO" at 1292,421.54 h50
  text "VDD" at 1184,421 h50
  text "PY-LINK V2.0" at 698,392.06 h60
Bottom Overlay:
Mechanical 1:
  lines w6: 215,1515 565,1515 585,1515 ; 215,1570 565,1570 585,1570 ; 1260,1515 1280,1515 1560,1515 ; 1260,1570 1280,1570 1560,1570
  lines w8: 0,0 ccw(c0,1) 1,1 1,3938.01 ; 215,1515 cw(c242.5,1542.5) 215,1570 ; 585,1515 ccw(c557.5,1542.5) 585,1570 ; 1260,1515 cw(c1287.5,1542.5) 1260,1570 ; 1560,1515 ccw(c1532.5,1542.5) 1560,1570

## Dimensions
1856.64,2.11 to 1850.64,3930.11 on Mechanical 1
42.5,1570 to 78.74,3929.06 on Mechanical 1
78.74,0 to -5,1505 on Mechanical 1
0,0 to 1770,-60 on Mechanical 1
